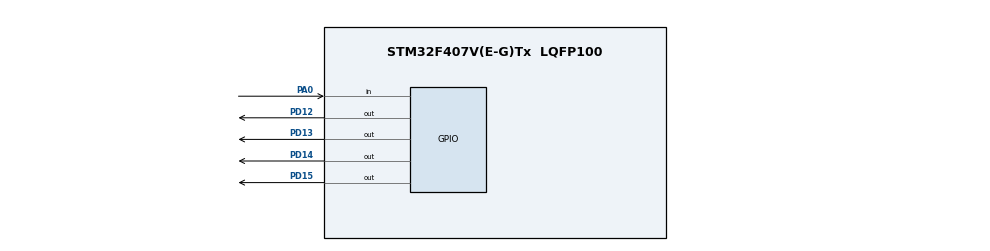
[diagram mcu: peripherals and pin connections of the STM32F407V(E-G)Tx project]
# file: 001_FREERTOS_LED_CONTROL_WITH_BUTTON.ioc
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Mcu.Family=STM32F4
Mcu.Name=STM32F407V(E-G)Tx
Mcu.Package=LQFP100
NVIC.PriorityGroup=NVIC_PRIORITYGROUP_4
PA0-WKUP.Signal=GPIO_Input
PD12.GPIO_Speed=GPIO_SPEED_FREQ_LOW
PD12.Signal=GPIO_Output
PD13.GPIO_Speed=GPIO_SPEED_FREQ_LOW
PD13.Signal=GPIO_Output
PD14.GPIO_Speed=GPIO_SPEED_FREQ_LOW
PD14.Signal=GPIO_Output
PD15.GPIO_Speed=GPIO_SPEED_FREQ_LOW
PD15.Signal=GPIO_Output
PH0-OSC_IN.Mode=HSE-External-Oscillator
PH0-OSC_IN.Signal=RCC_OSC_IN
PH1-OSC_OUT.Mode=HSE-External-Oscillator
PH1-OSC_OUT.Signal=RCC_OSC_OUT
ProjectManager.HeapSize=0x200
ProjectManager.StackSize=0x400
ProjectManager.TargetToolchain=STM32CubeIDE
RCC.48MHZClocksFreq_Value=32000000
RCC.AHBCLKDivider=RCC_SYSCLK_DIV4
RCC.AHBFreq_Value=16000000
RCC.APB1CLKDivider=RCC_HCLK_DIV4
RCC.APB1Freq_Value=4000000
RCC.APB1TimFreq_Value=8000000
RCC.APB2CLKDivider=RCC_HCLK_DIV2
RCC.APB2Freq_Value=8000000
RCC.APB2TimFreq_Value=16000000
RCC.CortexFreq_Value=16000000
RCC.EnbaleCSS=true
RCC.HCLKFreq_Value=16000000
RCC.HSE_VALUE=8000000
RCC.HSI_VALUE=16000000
RCC.LSE_VALUE=32768
RCC.PLLM=4
RCC.PLLN=64
RCC.PLLSourceVirtual=RCC_PLLSOURCE_HSE
RCC.SYSCLKFreq_VALUE=64000000
RCC.SYSCLKSource=RCC_SYSCLKSOURCE_PLLCLK
RCC.VCOOutputFreq_Value=128000000
board=custom

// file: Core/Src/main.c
/* USER CODE BEGIN Header */
/**
  ******************************************************************************
  * @file           : main.c
  * @brief          : Main program body
  ******************************************************************************
  * @attention
  *
  * <h2><center>&copy; Copyright (c) 2020 STMicroelectronics.
  * All rights reserved.</center></h2>
  *
  * This software component is licensed by ST under BSD 3-Clause license,
  * the "License"; You may not use this file except in compliance with the
  * License. You may obtain a copy of the License at:
  *                        opensource.org/licenses/BSD-3-Clause
  *
  ******************************************************************************
  */
/* USER CODE END Header */
#include "main.h"

/* USER CODE BEGIN Includes */
#include "FreeRTOS.h"
#include "task.h"

/* USER CODE END Includes */

/* USER CODE BEGIN PV */
uint8_t buttonCounter=0;
/* USER CODE END PV */

void SystemClock_Config(void);
static void MX_GPIO_Init(void);
/* USER CODE BEGIN PFP */
void myLedTask(void *params);
void myButtonTask(void *params);

/* USER CODE END PFP */

int main(void)
{

  /* MCU Configuration--------------------------------------------------------*/

  /* Reset of all peripherals, Initializes the Flash interface and the Systick. */
  HAL_Init();

  /* Configure the system clock */
  SystemClock_Config();

  /* Initialize all configured peripherals */
  MX_GPIO_Init();
  /* USER CODE BEGIN 2 */
  xTaskCreate(myLedTask, "Led_Task", 100, NULL, 1, NULL);
  xTaskCreate(myButtonTask, "Button_Task", 100, NULL, 1, NULL);

  vTaskStartScheduler();
  /* USER CODE END 2 */

  /* Infinite loop */
  while (1)
  {

  }
}

void SystemClock_Config(void)
{
  RCC_OscInitTypeDef RCC_OscInitStruct = {0};
  RCC_ClkInitTypeDef RCC_ClkInitStruct = {0};

  /** Configure the main internal regulator output voltage
  */
  __HAL_RCC_PWR_CLK_ENABLE();
  __HAL_PWR_VOLTAGESCALING_CONFIG(PWR_REGULATOR_VOLTAGE_SCALE1);
  /** Initializes the RCC Oscillators according to the specified parameters
  * in the RCC_OscInitTypeDef structure.
  */
  RCC_OscInitStruct.OscillatorType = RCC_OSCILLATORTYPE_HSI;
  RCC_OscInitStruct.HSIState = RCC_HSI_ON;
  RCC_OscInitStruct.HSICalibrationValue = RCC_HSICALIBRATION_DEFAULT;
  RCC_OscInitStruct.PLL.PLLState = RCC_PLL_NONE;
  if (HAL_RCC_OscConfig(&RCC_OscInitStruct) != HAL_OK)
  {
    Error_Handler();
  }
  /** Initializes the CPU, AHB and APB buses clocks
  */
  RCC_ClkInitStruct.ClockType = RCC_CLOCKTYPE_HCLK|RCC_CLOCKTYPE_SYSCLK
                              |RCC_CLOCKTYPE_PCLK1|RCC_CLOCKTYPE_PCLK2;
  RCC_ClkInitStruct.SYSCLKSource = RCC_SYSCLKSOURCE_HSI;
  RCC_ClkInitStruct.AHBCLKDivider = RCC_SYSCLK_DIV1;
  RCC_ClkInitStruct.APB1CLKDivider = RCC_HCLK_DIV4;
  RCC_ClkInitStruct.APB2CLKDivider = RCC_HCLK_DIV2;

  if (HAL_RCC_ClockConfig(&RCC_ClkInitStruct, FLASH_LATENCY_0) != HAL_OK)
  {
    Error_Handler();
  }
}

static void MX_GPIO_Init(void)
{
  GPIO_InitTypeDef GPIO_InitStruct = {0};

  /* GPIO Ports Clock Enable */
  __HAL_RCC_GPIOA_CLK_ENABLE();
  __HAL_RCC_GPIOD_CLK_ENABLE();

  /*Configure GPIO pin Output Level */
  HAL_GPIO_WritePin(GPIOD, GPIO_PIN_12|GPIO_PIN_13|GPIO_PIN_14|GPIO_PIN_15, GPIO_PIN_RESET);

  /*Configure GPIO pin : PA0 */
  GPIO_InitStruct.Pin = GPIO_PIN_0;
  GPIO_InitStruct.Mode = GPIO_MODE_INPUT;
  GPIO_InitStruct.Pull = GPIO_NOPULL;
  HAL_GPIO_Init(GPIOA, &GPIO_InitStruct);

  /*Configure GPIO pins : PD12 PD13 PD14 PD15 */
  GPIO_InitStruct.Pin = GPIO_PIN_12|GPIO_PIN_13|GPIO_PIN_14|GPIO_PIN_15;
  GPIO_InitStruct.Mode = GPIO_MODE_OUTPUT_PP;
  GPIO_InitStruct.Pull = GPIO_NOPULL;
  GPIO_InitStruct.Speed = GPIO_SPEED_FREQ_LOW;
  HAL_GPIO_Init(GPIOD, &GPIO_InitStruct);

}

/* USER CODE BEGIN 4 */
void myLedTask(void *params)
{
	while(1)
	{
		if(buttonCounter == 1)
		{
			HAL_GPIO_TogglePin(GPIOD, GPIO_PIN_All);
			vTaskDelay(1000);
		}
		else if(buttonCounter == 2)
		{
			HAL_GPIO_TogglePin(GPIOD, GPIO_PIN_All);
			vTaskDelay(750);
		}
		else if(buttonCounter == 3)
		{
			HAL_GPIO_TogglePin(GPIOD, GPIO_PIN_All);
			vTaskDelay(500);
		}
		else if(buttonCounter == 4)
		{
			HAL_GPIO_TogglePin(GPIOD, GPIO_PIN_All);
			vTaskDelay(250);
		}
		else if(buttonCounter == 0)
		{
			HAL_GPIO_WritePin(GPIOD, GPIO_PIN_All,DISABLE);
		}
	}
}
void myButtonTask(void *params)
{
	while(1)
	{
		if(HAL_GPIO_ReadPin(GPIOA, GPIO_PIN_0)==GPIO_PIN_SET)
		{
			while(HAL_GPIO_ReadPin(GPIOA, GPIO_PIN_0)==GPIO_PIN_SET);
			buttonCounter++;
			if(buttonCounter==5)
				buttonCounter=0;
		}
	}
}
/* USER CODE END 4 */

void Error_Handler(void)
{
  __disable_irq();
  while (1)
  {
  }
}

/************************ (C) COPYRIGHT STMicroelectronics *****END OF FILE****/
